VERSION 5.5 ;
NAMESCASESENSITIVE ON ;
BUSBITCHARS "[]" ;
DIVIDERCHAR "/" ;

PROPERTYDEFINITIONS
  LAYER routingPitch REAL ;
END PROPERTYDEFINITIONS

UNITS
  DATABASE MICRONS 1000 ;
END UNITS
MANUFACTURINGGRID 0.01 ;
LAYER POLY1
  TYPE MASTERSLICE ;
END POLY1

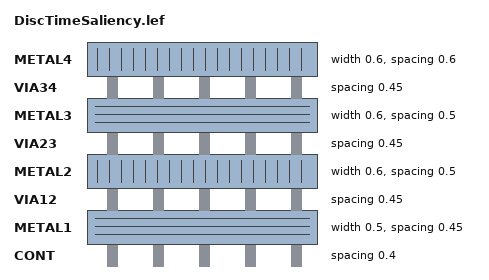
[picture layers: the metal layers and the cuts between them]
LAYER CONT
  TYPE CUT ;
  SPACING 0.4 ;
END CONT

LAYER METAL1
  TYPE ROUTING ;
  DIRECTION HORIZONTAL ;
  PITCH 0 ;
  WIDTH 0.5 ;
  SPACING 0.45 ;
  PROPERTY routingPitch 1.25 ;
END METAL1

LAYER VIA12
  TYPE CUT ;
  SPACING 0.45 ;
END VIA12

LAYER METAL2
  TYPE ROUTING ;
  DIRECTION VERTICAL ;
  PITCH 0 ;
  WIDTH 0.6 ;
  SPACING 0.5 ;
  PROPERTY routingPitch 1.4 ;
END METAL2

LAYER VIA23
  TYPE CUT ;
  SPACING 0.45 ;
END VIA23

LAYER METAL3
  TYPE ROUTING ;
  DIRECTION HORIZONTAL ;
  PITCH 0 ;
  WIDTH 0.6 ;
  SPACING 0.5 ;
  PROPERTY routingPitch 1.25 ;
END METAL3

LAYER VIA34
  TYPE CUT ;
  SPACING 0.45 ;
END VIA34

LAYER METAL4
  TYPE ROUTING ;
  DIRECTION VERTICAL ;
  PITCH 0 ;
  WIDTH 0.6 ;
  SPACING 0.6 ;
  PROPERTY routingPitch 1.4 ;
END METAL4

LAYER OVERLAP
  TYPE OVERLAP ;
END OVERLAP

VIARULE M4_M3 GENERATE
  LAYER METAL3 ;
    ENCLOSURE 0.2 0.2 ;
  LAYER METAL4 ;
    ENCLOSURE 0.15 0.15 ;
  LAYER VIA34 ;
    RECT -0.25 -0.25 0.25 0.25 ;
    SPACING 1 BY 1 ;
END M4_M3

VIARULE M3_M2 GENERATE
  LAYER METAL2 ;
    ENCLOSURE 0.2 0.2 ;
  LAYER METAL3 ;
    ENCLOSURE 0.15 0.15 ;
  LAYER VIA23 ;
    RECT -0.25 -0.25 0.25 0.25 ;
    SPACING 1 BY 1 ;
END M3_M2

VIARULE M2_M1 GENERATE
  LAYER METAL1 ;
    ENCLOSURE 0.2 0.2 ;
  LAYER METAL2 ;
    ENCLOSURE 0.15 0.15 ;
  LAYER VIA12 ;
    RECT -0.25 -0.25 0.25 0.25 ;
    SPACING 1 BY 1 ;
END M2_M1

VIARULE M1_POLY1 GENERATE
  LAYER POLY1 ;
    ENCLOSURE 0.2 0.2 ;
  LAYER METAL1 ;
    ENCLOSURE 0.15 0.15 ;
  LAYER CONT ;
    RECT -0.2 -0.2 0.2 0.2 ;
    SPACING 1 BY 1 ;
END M1_POLY1

VIA M1_POLY1
  LAYER CONT ;
    RECT -0.2 -0.2 0.2 0.2 ;
  LAYER POLY1 ;
    RECT -0.4 -0.4 0.4 0.4 ;
  LAYER METAL1 ;
    RECT -0.35 -0.35 0.35 0.35 ;
END M1_POLY1

VIA M2_M1
  LAYER VIA12 ;
    RECT -0.25 -0.25 0.25 0.25 ;
  LAYER METAL2 ;
    RECT -0.4 -0.4 0.4 0.4 ;
  LAYER METAL1 ;
    RECT -0.45 -0.45 0.45 0.45 ;
END M2_M1

VIA M3_M2
  LAYER VIA23 ;
    RECT -0.25 -0.25 0.25 0.25 ;
  LAYER METAL3 ;
    RECT -0.4 -0.4 0.4 0.4 ;
  LAYER METAL2 ;
    RECT -0.45 -0.45 0.45 0.45 ;
END M3_M2

VIA M4_M3
  LAYER VIA34 ;
    RECT -0.25 -0.25 0.25 0.25 ;
  LAYER METAL4 ;
    RECT -0.4 -0.4 0.4 0.4 ;
  LAYER METAL3 ;
    RECT -0.45 -0.45 0.45 0.45 ;
END M4_M3


MACRO TSMC350nm_VinjDecode2to4_vtile_spacing
END TSMC350nm_VinjDecode2to4_vtile_spacing

MACRO TSMC350nm_VinjDecode2to4_vtile_C_bridge
END TSMC350nm_VinjDecode2to4_vtile_C_bridge

MACRO TSMC350nm_VinjDecode2to4_vtile
  PIN Vinj
    DIRECTION INOUT ;
    USE SIGNAL ;
    PORT
      LAYER METAL1 ;
        RECT 7.78 11.04 9.06 11.45 ;
    END
  END Vinj
  PIN OUT<0>
    DIRECTION INOUT ;
    USE SIGNAL ;
    PORT
      LAYER METAL1 ;
        RECT 19.66 18.91 20.11 19.59 ;
    END
  END OUT<0>
  PIN OUT<1>
    DIRECTION INOUT ;
    USE SIGNAL ;
    PORT
      LAYER METAL1 ;
        RECT 19.66 13.41 20.12 14.1 ;
    END
  END OUT<1>
  PIN OUT<2>
    DIRECTION INOUT ;
    USE SIGNAL ;
    PORT
      LAYER METAL1 ;
        RECT 19.66 7.92 20.11 8.59 ;
    END
  END OUT<2>
  PIN OUT<3>
    DIRECTION INOUT ;
    USE SIGNAL ;
    PORT
      LAYER METAL1 ;
        RECT 19.66 2.41 20.11 3.09 ;
    END
  END OUT<3>
  PIN ENABLE
    DIRECTION INOUT ;
    USE SIGNAL ;
    PORT
      LAYER METAL1 ;
        RECT 0.01 3.48 0.71 4.21 ;
    END
  END ENABLE
  PIN GND
    DIRECTION INOUT ;
    USE SIGNAL ;
    PORT
      LAYER METAL1 ;
        RECT 19.52 5.0 20.12 5.99 ;
    END
  END GND
  PIN VINJ
    DIRECTION INOUT ;
    USE SIGNAL ;
    PORT
      LAYER METAL1 ;
        RECT 19.15 21.56 20.05 21.96 ;
    END
  END VINJ
  PIN IN<1>
    DIRECTION INOUT ;
    USE SIGNAL ;
    PORT
      LAYER METAL2 ;
        RECT 6.56 20.89 7.5 22.0 ;
    END
  END IN<1>
  PIN IN<0>
    DIRECTION INOUT ;
    USE SIGNAL ;
    PORT
      LAYER METAL2 ;
        RECT 3.9 20.96 4.5 22.0 ;
    END
  END IN<0>
END TSMC350nm_VinjDecode2to4_vtile

MACRO TSMC350nm_VinjDecode2to4_vtile_A_bridge
END TSMC350nm_VinjDecode2to4_vtile_A_bridge

MACRO TSMC350nm_VinjDecode2to4_vtile_bridge_spacing
END TSMC350nm_VinjDecode2to4_vtile_bridge_spacing

MACRO TSMC350nm_VinjDecode2to4_vtile_D_bridge
END TSMC350nm_VinjDecode2to4_vtile_D_bridge

MACRO TSMC350nm_VinjDecode2to4_vtile_B_bridge
END TSMC350nm_VinjDecode2to4_vtile_B_bridge

MACRO TSMC350nm_drainSelect01d3
  PIN Vinj
    DIRECTION INOUT ;
    USE SIGNAL ;
    PORT
      LAYER METAL1 ;
        RECT 6.12 21.55 7.4 21.96 ;
    END
  END Vinj
  PIN VINJ
    DIRECTION INOUT ;
    USE SIGNAL ;
    PORT
      LAYER METAL1 ;
        RECT 6.12 21.55 7.4 21.96 ;
    END
  END VINJ
  PIN GND
    DIRECTION INOUT ;
    USE SIGNAL ;
    PORT
      LAYER METAL1 ;
        RECT 8.76 16.56 9.51 16.97 ;
    END
  END GND
  PIN DRAIN4
    DIRECTION INOUT ;
    USE SIGNAL ;
    PORT
      LAYER METAL1 ;
        RECT 15.99 2.54 16.66 2.97 ;
    END
  END DRAIN4
  PIN DRAIN3
    DIRECTION INOUT ;
    USE SIGNAL ;
    PORT
      LAYER METAL1 ;
        RECT 15.99 8.03 16.66 8.46 ;
    END
  END DRAIN3
  PIN DRAIN2
    DIRECTION INOUT ;
    USE SIGNAL ;
    PORT
      LAYER METAL1 ;
        RECT 15.99 13.54 16.66 13.97 ;
    END
  END DRAIN2
  PIN DRAIN1
    DIRECTION INOUT ;
    USE SIGNAL ;
    PORT
      LAYER METAL1 ;
        RECT 15.99 19.03 16.66 19.46 ;
    END
  END DRAIN1
  PIN SELECT<3>
    DIRECTION INOUT ;
    USE SIGNAL ;
    PORT
      LAYER METAL1 ;
        RECT 0.0 2.54 0.67 2.97 ;
    END
  END SELECT<3>
  PIN SELET<2>
    DIRECTION INOUT ;
    USE SIGNAL ;
    PORT
      LAYER METAL1 ;
        RECT 0.0 8.03 0.67 8.46 ;
    END
  END SELET<2>
  PIN SELECT<1>
    DIRECTION INOUT ;
    USE SIGNAL ;
    PORT
      LAYER METAL1 ;
        RECT 0.0 13.54 0.67 13.97 ;
    END
  END SELECT<1>
  PIN SELECT<0>
    DIRECTION INOUT ;
    USE SIGNAL ;
    PORT
      LAYER METAL1 ;
        RECT 0.0 19.03 0.67 19.46 ;
    END
  END SELECT<0>
  PIN DRAINRAIL
    DIRECTION INOUT ;
    USE SIGNAL ;
    PORT
      LAYER METAL2 ;
        RECT 7.47 21.56 8.25 21.99 ;
    END
  END DRAINRAIL
END TSMC350nm_drainSelect01d3

MACRO TSMC350nm_FourTgate_ThickOx_FG_MEM
  PIN B<2>
    DIRECTION INOUT ;
    USE SIGNAL ;
    PORT
      LAYER METAL1 ;
        RECT 9.75 7.01 10.31 7.44 ;
    END
  END B<2>
  PIN A<2>
    DIRECTION INOUT ;
    USE SIGNAL ;
    PORT
      LAYER METAL1 ;
        RECT 0.0 8.0 0.7 8.5 ;
    END
  END A<2>
  PIN B<3>
    DIRECTION INOUT ;
    USE SIGNAL ;
    PORT
      LAYER METAL1 ;
        RECT 9.75 2.15 10.31 2.58 ;
    END
  END B<3>
  PIN A<3>
    DIRECTION INOUT ;
    USE SIGNAL ;
    PORT
      LAYER METAL1 ;
        RECT 0.0 2.5 0.7 3.0 ;
    END
  END A<3>
  PIN GND
    DIRECTION INOUT ;
    USE SIGNAL ;
    PORT
      LAYER METAL1 ;
        RECT 1.61 16.56 2.36 16.97 ;
    END
  END GND
  PIN B<0>
    DIRECTION INOUT ;
    USE SIGNAL ;
    PORT
      LAYER METAL1 ;
        RECT 9.75 20.33 10.31 20.76 ;
    END
  END B<0>
  PIN A<0>
    DIRECTION INOUT ;
    USE SIGNAL ;
    PORT
      LAYER METAL1 ;
        RECT 0.0 19.0 0.7 19.5 ;
    END
  END A<0>
  PIN B<1>
    DIRECTION INOUT ;
    USE SIGNAL ;
    PORT
      LAYER METAL1 ;
        RECT 9.75 14.73 10.31 15.16 ;
    END
  END B<1>
  PIN A<1>
    DIRECTION INOUT ;
    USE SIGNAL ;
    PORT
      LAYER METAL1 ;
        RECT 0.0 13.5 0.7 14.0 ;
    END
  END A<1>
  PIN SelBar
    DIRECTION INOUT ;
    USE SIGNAL ;
    PORT
      LAYER METAL2 ;
        RECT 3.41 21.12 4.21 22.0 ;
    END
  END SelBar
  PIN Sel
    DIRECTION INOUT ;
    USE SIGNAL ;
    PORT
      LAYER METAL2 ;
        RECT 4.8 21.12 5.6 22.0 ;
    END
  END Sel
  PIN VINJ
    DIRECTION INOUT ;
    USE SIGNAL ;
    PORT
      LAYER METAL2 ;
        RECT 6.26 21.78 7.06 22.0 ;
    END
  END VINJ
END TSMC350nm_FourTgate_ThickOx_FG_MEM

MACRO TSMC350nm_IndirectSwitches
  PIN GND_T
    DIRECTION INOUT ;
    USE SIGNAL ;
    PORT
      LAYER METAL2 ;
        RECT 15.4 21.0 16.2 22.0 ;
    END
  END GND_T
  PIN VINJ_T
    DIRECTION INOUT ;
    USE SIGNAL ;
    PORT
      LAYER METAL2 ;
        RECT 6.3 21.04 7.32 22.0 ;
    END
  END VINJ_T
  PIN VDD<1>
    DIRECTION INOUT ;
    USE SIGNAL ;
    PORT
      LAYER METAL2 ;
        RECT 24.5 0.0 25.1 0.75 ;
    END
  END VDD<1>
  PIN VTUN
    DIRECTION INOUT ;
    USE SIGNAL ;
    PORT
      LAYER METAL2 ;
        RECT 13.3 0.0 13.9 0.82 ;
    END
  END VTUN
  PIN GND<0>
    DIRECTION INOUT ;
    USE SIGNAL ;
    PORT
      LAYER METAL2 ;
        RECT 11.2 0.0 11.8 0.85 ;
    END
  END GND<0>
  PIN GNDV<1>
    DIRECTION INOUT ;
    USE SIGNAL ;
    PORT
      LAYER METAL2 ;
        RECT 15.47 0.0 15.95 1.0 ;
    END
  END GNDV<1>
  PIN VINJ
    DIRECTION INOUT ;
    USE SIGNAL ;
    PORT
      LAYER METAL2 ;
        RECT 4.2 0.0 4.8 1.0 ;
    END
  END VINJ
  PIN VDD<0>
    DIRECTION INOUT ;
    USE SIGNAL ;
    PORT
      LAYER METAL2 ;
        RECT 2.1 0.0 2.7 1.09 ;
    END
  END VDD<0>
  PIN Vg<0>
    DIRECTION INOUT ;
    USE SIGNAL ;
    PORT
      LAYER METAL2 ;
        RECT 8.4 0.005 9.0 0.825 ;
    END
  END Vg<0>
  PIN CTRL_B<0>
    DIRECTION INOUT ;
    USE SIGNAL ;
    PORT
      LAYER METAL2 ;
        RECT 6.3 0.01 6.9 0.76 ;
    END
  END CTRL_B<0>
  PIN CTRL_B<1>
    DIRECTION INOUT ;
    USE SIGNAL ;
    PORT
      LAYER METAL2 ;
        RECT 20.3 0.01 20.9 0.75 ;
    END
  END CTRL_B<1>
  PIN Vg<1>
    DIRECTION INOUT ;
    USE SIGNAL ;
    PORT
      LAYER METAL2 ;
        RECT 18.2 0.0 18.8 0.76 ;
    END
  END Vg<1>
  PIN decode<0>
    DIRECTION INOUT ;
    USE SIGNAL ;
    PORT
      LAYER METAL2 ;
        RECT 3.46 21.16 4.8 22.0 ;
    END
  END decode<0>
  PIN RUN_IN<1>
    DIRECTION INOUT ;
    USE SIGNAL ;
    PORT
      LAYER METAL2 ;
        RECT 17.5 21.01 18.1 22.0 ;
    END
  END RUN_IN<1>
  PIN RUN_IN<0>
    DIRECTION INOUT ;
    USE SIGNAL ;
    PORT
      LAYER METAL2 ;
        RECT 10.5 20.9 11.1 22.0 ;
    END
  END RUN_IN<0>
  PIN VPWR<1>
    DIRECTION INOUT ;
    USE SIGNAL ;
    PORT
      LAYER METAL2 ;
        RECT 21.7 21.08 22.3 22.0 ;
    END
  END VPWR<1>
  PIN decode<1>
    DIRECTION INOUT ;
    USE SIGNAL ;
    PORT
      LAYER METAL2 ;
        RECT 23.8 21.09 25.0 22.0 ;
    END
  END decode<1>
  PIN VPWR<0>
    DIRECTION INOUT ;
    USE SIGNAL ;
    PORT
      LAYER METAL2 ;
        RECT 1.71 21.21 2.43 22.0 ;
    END
  END VPWR<0>
  PIN VTUN_T
    DIRECTION INOUT ;
    USE SIGNAL ;
    PORT
      LAYER METAL2 ;
        RECT 12.6 21.12 13.7 22.0 ;
    END
  END VTUN_T
  PIN vtun_l
    DIRECTION INOUT ;
    USE SIGNAL ;
    PORT
      LAYER METAL1 ;
        RECT 0.0 0.9 1.31 1.88 ;
    END
  END vtun_l
  PIN vtun_r
    DIRECTION INOUT ;
    USE SIGNAL ;
    PORT
      LAYER METAL1 ;
        RECT 26.17 0.9 27.46 2.17 ;
    END
  END vtun_r
  PIN vgsel_r
    DIRECTION INOUT ;
    USE SIGNAL ;
    PORT
      LAYER METAL1 ;
        RECT 26.52 3.15 27.46 4.45 ;
    END
  END vgsel_r
  PIN prog_r
    DIRECTION INOUT ;
    USE SIGNAL ;
    PORT
      LAYER METAL1 ;
        RECT 26.59 9.15 27.46 10.55 ;
    END
  END prog_r
  PIN run_r
    DIRECTION INOUT ;
    USE SIGNAL ;
    PORT
      LAYER METAL1 ;
        RECT 26.28 6.05 27.46 7.29 ;
    END
  END run_r
  PIN RUN
    DIRECTION INOUT ;
    USE SIGNAL ;
    PORT
      LAYER METAL1 ;
        RECT 0.0 6.05 0.91 7.29 ;
    END
  END RUN
  PIN PROG
    DIRECTION INOUT ;
    USE SIGNAL ;
    PORT
      LAYER METAL1 ;
        RECT 0.0 9.15 0.87 10.55 ;
    END
  END PROG
  PIN Vgsel
    DIRECTION INOUT ;
    USE SIGNAL ;
    PORT
      LAYER METAL1 ;
        RECT 0.0 3.72 0.91 4.45 ;
    END
  END Vgsel
END TSMC350nm_IndirectSwitches

MACRO TSMC350nm_VinjDecode2to4_htile
  PIN IN<1>
    DIRECTION INOUT ;
    USE SIGNAL ;
    PORT
      LAYER METAL1 ;
        RECT 0.0 11.85 0.9 12.74 ;
    END
  END IN<1>
  PIN IN<0>
    DIRECTION INOUT ;
    USE SIGNAL ;
    PORT
      LAYER METAL1 ;
        RECT 0.0 10.13 0.87 11.1 ;
    END
  END IN<0>
  PIN VINJ
    DIRECTION INOUT ;
    USE SIGNAL ;
    PORT
      LAYER METAL1 ;
        RECT 0.0 1.99 0.5 2.49 ;
    END
  END VINJ
  PIN GND
    DIRECTION INOUT ;
    USE SIGNAL ;
    PORT
      LAYER METAL1 ;
        RECT 0.0 6.99 0.51 7.49 ;
    END
  END GND
  PIN GND_b<1>
    DIRECTION INOUT ;
    USE SIGNAL ;
    PORT
      LAYER METAL2 ;
        RECT 40.32 0.0 40.92 1.79 ;
    END
  END GND_b<1>
  PIN VINJ_b<1>
    DIRECTION INOUT ;
    USE SIGNAL ;
    PORT
      LAYER METAL2 ;
        RECT 22.1 0.0 22.7 1.44 ;
    END
  END VINJ_b<1>
  PIN GND_b<0>
    DIRECTION INOUT ;
    USE SIGNAL ;
    PORT
      LAYER METAL2 ;
        RECT 18.85 0.0 19.45 1.41 ;
    END
  END GND_b<0>
  PIN VINJ_b<0>
    DIRECTION INOUT ;
    USE SIGNAL ;
    PORT
      LAYER METAL2 ;
        RECT 1.07 0.0 1.67 1.25 ;
    END
  END VINJ_b<0>
  PIN VINJV
    DIRECTION INOUT ;
    USE SIGNAL ;
    PORT
      LAYER METAL2 ;
        RECT 23.7 21.26 24.31 22.0 ;
    END
  END VINJV
  PIN GNDV
    DIRECTION INOUT ;
    USE SIGNAL ;
    PORT
      LAYER METAL2 ;
        RECT 25.84 21.28 26.44 22.0 ;
    END
  END GNDV
  PIN RUN_OUT<3>
    DIRECTION INOUT ;
    USE SIGNAL ;
    PORT
      LAYER METAL2 ;
        RECT 34.39 0.0 35.19 0.86 ;
    END
  END RUN_OUT<3>
  PIN RUN_OUT<2>
    DIRECTION INOUT ;
    USE SIGNAL ;
    PORT
      LAYER METAL2 ;
        RECT 28.77 0.0 29.57 0.86 ;
    END
  END RUN_OUT<2>
  PIN RUN_OUT<1>
    DIRECTION INOUT ;
    USE SIGNAL ;
    PORT
      LAYER METAL2 ;
        RECT 13.5 0.0 14.1 0.86 ;
    END
  END RUN_OUT<1>
  PIN RUN_OUT<0>
    DIRECTION INOUT ;
    USE SIGNAL ;
    PORT
      LAYER METAL2 ;
        RECT 7.34 0.0 8.14 0.86 ;
    END
  END RUN_OUT<0>
  PIN ENABLE
    DIRECTION INOUT ;
    USE SIGNAL ;
    PORT
      LAYER METAL2 ;
        RECT 6.29 21.66 6.89 22.0 ;
    END
  END ENABLE
  PIN OUT<2>
    DIRECTION INOUT ;
    USE SIGNAL ;
    PORT
      LAYER METAL2 ;
        RECT 25.28 0.0 25.87 0.87 ;
    END
  END OUT<2>
  PIN OUT<3>
    DIRECTION INOUT ;
    USE SIGNAL ;
    PORT
      LAYER METAL2 ;
        RECT 37.14 0.0 37.73 0.83 ;
    END
  END OUT<3>
  PIN OUT<0>
    DIRECTION INOUT ;
    USE SIGNAL ;
    PORT
      LAYER METAL2 ;
        RECT 4.27 0.0 4.87 0.86 ;
    END
  END OUT<0>
  PIN OUT<1>
    DIRECTION INOUT ;
    USE SIGNAL ;
    PORT
      LAYER METAL2 ;
        RECT 16.14 0.0 16.72 0.85 ;
    END
  END OUT<1>
  PIN VGRUN<0>
    DIRECTION INOUT ;
    USE SIGNAL ;
    PORT
      LAYER METAL2 ;
        RECT 9.1 21.59 9.7 22.0 ;
    END
  END VGRUN<0>
  PIN VGRUN<1>
    DIRECTION INOUT ;
    USE SIGNAL ;
    PORT
      LAYER METAL2 ;
        RECT 11.2 21.6 11.8 22.0 ;
    END
  END VGRUN<1>
  PIN VGRUN<2>
    DIRECTION INOUT ;
    USE SIGNAL ;
    PORT
      LAYER METAL2 ;
        RECT 28.7 21.71 29.3 22.0 ;
    END
  END VGRUN<2>
  PIN VGRUN<3>
    DIRECTION INOUT ;
    USE SIGNAL ;
    PORT
      LAYER METAL2 ;
        RECT 33.6 21.54 34.2 22.0 ;
    END
  END VGRUN<3>
END TSMC350nm_VinjDecode2to4_htile

MACRO TSMC350nm_VinjDecode2to4_htile_A_bridge
  PIN VGRUN<3>
    DIRECTION INOUT ;
    USE SIGNAL ;
    PORT
      LAYER METAL2 ;
        RECT 34.5 9.46 35.1 10.0 ;
    END
  END VGRUN<3>
  PIN VGRUN<2>
    DIRECTION INOUT ;
    USE SIGNAL ;
    PORT
      LAYER METAL2 ;
        RECT 26.6 9.56 27.2 10.0 ;
    END
  END VGRUN<2>
  PIN VGRUN<1>
    DIRECTION INOUT ;
    USE SIGNAL ;
    PORT
      LAYER METAL2 ;
        RECT 13.5 9.46 14.1 10.0 ;
    END
  END VGRUN<1>
  PIN VGRUN<0>
    DIRECTION INOUT ;
    USE SIGNAL ;
    PORT
      LAYER METAL2 ;
        RECT 5.6 9.52 6.2 10.0 ;
    END
  END VGRUN<0>
END TSMC350nm_VinjDecode2to4_htile_A_bridge

MACRO TSMC350nm_VinjDecode2to4_htile_B_bridge
  PIN VGRUN<0>
    DIRECTION INOUT ;
    USE SIGNAL ;
    PORT
      LAYER METAL2 ;
        RECT 9.1 9.52 9.7 10.0 ;
    END
  END VGRUN<0>
  PIN VGRUN<1>
    DIRECTION INOUT ;
    USE SIGNAL ;
    PORT
      LAYER METAL2 ;
        RECT 11.2 9.52 11.8 10.0 ;
    END
  END VGRUN<1>
  PIN VGRUN<2>
    DIRECTION INOUT ;
    USE SIGNAL ;
    PORT
      LAYER METAL2 ;
        RECT 28.7 9.5 29.3 10.0 ;
    END
  END VGRUN<2>
  PIN VGRUN<3>
    DIRECTION INOUT ;
    USE SIGNAL ;
    PORT
      LAYER METAL2 ;
        RECT 33.6 9.51 34.2 10.0 ;
    END
  END VGRUN<3>
END TSMC350nm_VinjDecode2to4_htile_B_bridge

MACRO TSMC350nm_VinjDecode2to4_htile_C_bridge
  PIN VGRUN<0>
    DIRECTION INOUT ;
    USE SIGNAL ;
    PORT
      LAYER METAL2 ;
        RECT 9.1 9.54 9.7 10.0 ;
    END
  END VGRUN<0>
  PIN VGRUN<1>
    DIRECTION INOUT ;
    USE SIGNAL ;
    PORT
      LAYER METAL2 ;
        RECT 11.2 9.57 11.8 10.0 ;
    END
  END VGRUN<1>
  PIN VGRUN<2>
    DIRECTION INOUT ;
    USE SIGNAL ;
    PORT
      LAYER METAL2 ;
        RECT 28.7 9.59 29.3 10.0 ;
    END
  END VGRUN<2>
  PIN VGRUN<3>
    DIRECTION INOUT ;
    USE SIGNAL ;
    PORT
      LAYER METAL2 ;
        RECT 33.6 9.57 34.2 10.0 ;
    END
  END VGRUN<3>
END TSMC350nm_VinjDecode2to4_htile_C_bridge

MACRO TSMC350nm_VinjDecode2to4_htile_D_bridge
  PIN VGRUN<0>
    DIRECTION INOUT ;
    USE SIGNAL ;
    PORT
      LAYER METAL2 ;
        RECT 9.1 9.58 9.7 10.0 ;
    END
  END VGRUN<0>
  PIN VGRUN<1>
    DIRECTION INOUT ;
    USE SIGNAL ;
    PORT
      LAYER METAL2 ;
        RECT 11.2 9.55 11.8 10.0 ;
    END
  END VGRUN<1>
  PIN VGRUN<2>
    DIRECTION INOUT ;
    USE SIGNAL ;
    PORT
      LAYER METAL2 ;
        RECT 28.7 9.58 29.3 10.0 ;
    END
  END VGRUN<2>
  PIN VGRUN<3>
    DIRECTION INOUT ;
    USE SIGNAL ;
    PORT
      LAYER METAL2 ;
        RECT 33.6 9.57 34.2 10.0 ;
    END
  END VGRUN<3>
END TSMC350nm_VinjDecode2to4_htile_D_bridge

MACRO TSMC350nm_VinjDecode2to4_htile_spacing
  PIN VGRUN<0>
    DIRECTION INOUT ;
    USE SIGNAL ;
    PORT
      LAYER METAL2 ;
        RECT 9.1 21.59 9.7 22.0 ;
    END
  END VGRUN<0>
  PIN VGRUN<1>
    DIRECTION INOUT ;
    USE SIGNAL ;
    PORT
      LAYER METAL2 ;
        RECT 11.2 21.52 11.8 22.0 ;
    END
  END VGRUN<1>
  PIN VGRUN<2>
    DIRECTION INOUT ;
    USE SIGNAL ;
    PORT
      LAYER METAL2 ;
        RECT 28.7 21.54 29.3 22.0 ;
    END
  END VGRUN<2>
  PIN VGRUN<3>
    DIRECTION INOUT ;
    USE SIGNAL ;
    PORT
      LAYER METAL2 ;
        RECT 33.6 21.55 34.2 22.0 ;
    END
  END VGRUN<3>
END TSMC350nm_VinjDecode2to4_htile_spacing

MACRO TSMC350nm_VinjDecode2to4_htile_bridge_spacing
  PIN VGRUN<0>
    DIRECTION INOUT ;
    USE SIGNAL ;
    PORT
      LAYER METAL2 ;
        RECT 9.1 9.52 9.7 9.99 ;
    END
  END VGRUN<0>
  PIN VGRUN<1>
    DIRECTION INOUT ;
    USE SIGNAL ;
    PORT
      LAYER METAL2 ;
        RECT 11.2 9.51 11.8 9.99 ;
    END
  END VGRUN<1>
  PIN VGRUN<2>
    DIRECTION INOUT ;
    USE SIGNAL ;
    PORT
      LAYER METAL2 ;
        RECT 28.7 9.41 29.3 9.99 ;
    END
  END VGRUN<2>
  PIN VGRUN<3>
    DIRECTION INOUT ;
    USE SIGNAL ;
    PORT
      LAYER METAL2 ;
        RECT 33.6 9.47 34.2 9.99 ;
    END
  END VGRUN<3>
END TSMC350nm_VinjDecode2to4_htile_bridge_spacing

MACRO SampleControl
  PIN Sample
    DIRECTION INOUT ;
    USE SIGNAL ;
    PORT
      LAYER METAL1 ;
        RECT 0.0 30.1 1.4 31.5 ;
    END
  END Sample
  PIN VDD
    DIRECTION INOUT ;
    USE SIGNAL ;
    PORT
      LAYER METAL1 ;
        RECT 0.0 36.65 1.4 38.05 ;
    END
  END VDD
  PIN Q
    DIRECTION INOUT ;
    USE SIGNAL ;
    PORT
      LAYER METAL2 ;
        RECT 22.2 14.85 22.8 15.45 ;
    END
  END Q
  PIN CLK
    DIRECTION INOUT ;
    USE SIGNAL ;
    PORT
      LAYER METAL2 ;
        RECT 0.0 12.75 0.6 13.35 ;
    END
  END CLK
  PIN D
    DIRECTION INOUT ;
    USE SIGNAL ;
    PORT
      LAYER METAL2 ;
        RECT 0.0 14.85 0.6 15.45 ;
    END
  END D
  PIN GND
    DIRECTION INOUT ;
    USE SIGNAL ;
    PORT
      LAYER METAL2 ;
        RECT 13.08 39.4 13.68 40.0 ;
    END
  END GND
  PIN phi2
    DIRECTION INOUT ;
    USE SIGNAL ;
    PORT
      LAYER METAL2 ;
        RECT 11.45 39.4 12.05 40.0 ;
    END
  END phi2
  PIN phi1
    DIRECTION INOUT ;
    USE SIGNAL ;
    PORT
      LAYER METAL2 ;
        RECT 2.1 39.4 2.7 40.0 ;
    END
  END phi1
END SampleControl

MACRO tile_analog_frame
  PIN n_Prog
    DIRECTION INOUT ;
    USE SIGNAL ;
    PORT
      LAYER METAL3 ;
        RECT 13.3 3722.3 14.7 3725.1 ;
    END
  END n_Prog
  PIN n_RUN
    DIRECTION INOUT ;
    USE SIGNAL ;
    PORT
      LAYER METAL3 ;
        RECT 27.3 3722.3 28.7 3725.1 ;
    END
  END n_RUN
  PIN n_VGPROG
    DIRECTION INOUT ;
    USE SIGNAL ;
    PORT
      LAYER METAL3 ;
        RECT 41.3 3722.3 42.7 3725.1 ;
    END
  END n_VGPROG
  PIN n_avdd
    DIRECTION INOUT ;
    USE SIGNAL ;
    PORT
      LAYER METAL3 ;
        RECT 5747.51 3722.3 5748.91 3725.1 ;
    END
  END n_avdd
  PIN n_gnd
    DIRECTION INOUT ;
    USE SIGNAL ;
    PORT
      LAYER METAL3 ;
        RECT 5733.51 3722.3 5734.91 3725.1 ;
    END
  END n_gnd
  PIN n_vinj
    DIRECTION INOUT ;
    USE SIGNAL ;
    PORT
      LAYER METAL3 ;
        RECT 5719.51 3722.3 5720.91 3725.1 ;
    END
  END n_vinj
  PIN n_Q_enable
    DIRECTION INOUT ;
    USE SIGNAL ;
    PORT
      LAYER METAL3 ;
        RECT 55.3 3722.3 56.7 3725.1 ;
    END
  END n_Q_enable
  PIN e_vbias
    DIRECTION INOUT ;
    USE SIGNAL ;
    PORT
      LAYER METAL3 ;
        RECT 5774.11 3709.7 5776.91 3711.1 ;
    END
  END e_vbias
  PIN e_vdbias
    DIRECTION INOUT ;
    USE SIGNAL ;
    PORT
      LAYER METAL3 ;
        RECT 5774.11 3695.7 5776.91 3697.1 ;
    END
  END e_vdbias
  PIN e_vgbias
    DIRECTION INOUT ;
    USE SIGNAL ;
    PORT
      LAYER METAL3 ;
        RECT 5774.11 3681.7 5776.91 3683.1 ;
    END
  END e_vgbias
  PIN s_avdd
    DIRECTION INOUT ;
    USE SIGNAL ;
    PORT
      LAYER METAL3 ;
        RECT 5747.51 0.0 5748.91 2.8 ;
    END
  END s_avdd
  PIN s_gnd
    DIRECTION INOUT ;
    USE SIGNAL ;
    PORT
      LAYER METAL3 ;
        RECT 5733.51 0.0 5734.91 2.8 ;
    END
  END s_gnd
  PIN s_vinj
    DIRECTION INOUT ;
    USE SIGNAL ;
    PORT
      LAYER METAL3 ;
        RECT 5719.51 0.0 5720.91 2.8 ;
    END
  END s_vinj
  PIN s_CLK
    DIRECTION INOUT ;
    USE SIGNAL ;
    PORT
      LAYER METAL3 ;
        RECT 13.3 0.0 14.7 2.8 ;
    END
  END s_CLK
  PIN s_Sample
    DIRECTION INOUT ;
    USE SIGNAL ;
    PORT
      LAYER METAL3 ;
        RECT 27.3 0.0 28.7 2.8 ;
    END
  END s_Sample
  PIN s_Q
    DIRECTION INOUT ;
    USE SIGNAL ;
    PORT
      LAYER METAL3 ;
        RECT 41.3 0.0 42.7 2.8 ;
    END
  END s_Q
  PIN s_D
    DIRECTION INOUT ;
    USE SIGNAL ;
    PORT
      LAYER METAL3 ;
        RECT 55.3 0.0 56.7 2.8 ;
    END
  END s_D
END tile_analog_frame

MACRO dotproduct_mid
  PIN phi1_B
    DIRECTION INOUT ;
    USE SIGNAL ;
    PORT
      LAYER METAL2 ;
        RECT 2.1 0.0 2.7 0.6 ;
    END
  END phi1_B
  PIN GND_B
    DIRECTION INOUT ;
    USE SIGNAL ;
    PORT
      LAYER METAL2 ;
        RECT 13.08 0.0 13.68 0.6 ;
    END
  END GND_B
  PIN phi2_B
    DIRECTION INOUT ;
    USE SIGNAL ;
    PORT
      LAYER METAL2 ;
        RECT 11.45 0.0 12.05 0.6 ;
    END
  END phi2_B
  PIN GND
    DIRECTION INOUT ;
    USE SIGNAL ;
    PORT
      LAYER METAL2 ;
        RECT 13.08 21.4 13.68 22.0 ;
    END
  END GND
  PIN out2
    DIRECTION INOUT ;
    USE SIGNAL ;
    PORT
      LAYER METAL2 ;
        RECT 17.05 21.4 17.65 22.0 ;
    END
  END out2
  PIN out1
    DIRECTION INOUT ;
    USE SIGNAL ;
    PORT
      LAYER METAL2 ;
        RECT 6.95 21.4 7.55 22.0 ;
    END
  END out1
  PIN phi2
    DIRECTION INOUT ;
    USE SIGNAL ;
    PORT
      LAYER METAL2 ;
        RECT 11.45 21.4 12.05 22.0 ;
    END
  END phi2
  PIN phi1
    DIRECTION INOUT ;
    USE SIGNAL ;
    PORT
      LAYER METAL2 ;
        RECT 2.1 21.4 2.7 22.0 ;
    END
  END phi1
  PIN Q<0>
    DIRECTION INOUT ;
    USE SIGNAL ;
    PORT
      LAYER METAL1 ;
        RECT 0.0 16.61 1.4 18.01 ;
    END
  END Q<0>
  PIN Q<3>
    DIRECTION INOUT ;
    USE SIGNAL ;
    PORT
      LAYER METAL1 ;
        RECT 0.0 4.01 1.4 5.41 ;
    END
  END Q<3>
  PIN Q<1>
    DIRECTION INOUT ;
    USE SIGNAL ;
    PORT
      LAYER METAL1 ;
        RECT 0.0 14.76 1.4 16.16 ;
    END
  END Q<1>
  PIN Q<2>
    DIRECTION INOUT ;
    USE SIGNAL ;
    PORT
      LAYER METAL1 ;
        RECT 0.0 5.86 1.4 7.26 ;
    END
  END Q<2>
  PIN K<2>
    DIRECTION INOUT ;
    USE SIGNAL ;
    PORT
      LAYER METAL1 ;
        RECT 20.6 9.31 22.0 10.71 ;
    END
  END K<2>
  PIN K<1>
    DIRECTION INOUT ;
    USE SIGNAL ;
    PORT
      LAYER METAL1 ;
        RECT 20.6 11.31 22.0 12.71 ;
    END
  END K<1>
  PIN K<3>
    DIRECTION INOUT ;
    USE SIGNAL ;
    PORT
      LAYER METAL1 ;
        RECT 20.6 0.56 22.0 1.96 ;
    END
  END K<3>
  PIN K<0>
    DIRECTION INOUT ;
    USE SIGNAL ;
    PORT
      LAYER METAL1 ;
        RECT 20.6 20.06 22.0 21.46 ;
    END
  END K<0>
END dotproduct_mid

MACRO TSMC350nm_4x2_Indirect
  PIN Vg<1>
    DIRECTION INOUT ;
    USE SIGNAL ;
    PORT
      LAYER METAL2 ;
        RECT 18.2 21.06 18.8 22.0 ;
    END
  END Vg<1>
  PIN Vsel<1>
    DIRECTION INOUT ;
    USE SIGNAL ;
    PORT
      LAYER METAL2 ;
        RECT 20.3 21.08 20.9 22.0 ;
    END
  END Vsel<1>
  PIN VINJ<1>
    DIRECTION INOUT ;
    USE SIGNAL ;
    PORT
      LAYER METAL2 ;
        RECT 22.4 21.05 23.0 22.0 ;
    END
  END VINJ<1>
  PIN Vsel<0>
    DIRECTION INOUT ;
    USE SIGNAL ;
    PORT
      LAYER METAL2 ;
        RECT 6.3 21.2 6.9 22.0 ;
    END
  END Vsel<0>
  PIN Vs<0>
    DIRECTION INOUT ;
    USE SIGNAL ;
    PORT
      LAYER METAL2 ;
        RECT 2.1 21.21 2.7 22.0 ;
    END
  END Vs<0>
  PIN Vs<1>
    DIRECTION INOUT ;
    USE SIGNAL ;
    PORT
      LAYER METAL2 ;
        RECT 24.5 21.06 25.1 22.0 ;
    END
  END Vs<1>
  PIN VTUN
    DIRECTION INOUT ;
    USE SIGNAL ;
    PORT
      LAYER METAL2 ;
        RECT 13.3 21.09 13.9 22.0 ;
    END
  END VTUN
  PIN VINJ<0>
    DIRECTION INOUT ;
    USE SIGNAL ;
    PORT
      LAYER METAL2 ;
        RECT 4.2 21.18 4.8 22.0 ;
    END
  END VINJ<0>
  PIN GND<0>
    DIRECTION INOUT ;
    USE SIGNAL ;
    PORT
      LAYER METAL2 ;
        RECT 11.2 21.07 11.8 22.0 ;
    END
  END GND<0>
  PIN Vg<0>
    DIRECTION INOUT ;
    USE SIGNAL ;
    PORT
      LAYER METAL2 ;
        RECT 8.4 21.03 9.0 22.0 ;
    END
  END Vg<0>
  PIN GND<1>
    DIRECTION INOUT ;
    USE SIGNAL ;
    PORT
      LAYER METAL2 ;
        RECT 15.41 21.06 16.01 22.0 ;
    END
  END GND<1>
  PIN Vs_b<0>
    DIRECTION INOUT ;
    USE SIGNAL ;
    PORT
      LAYER METAL2 ;
        RECT 1.42 0.0 2.7 0.6 ;
    END
  END Vs_b<0>
  PIN VINJ_b<0>
    DIRECTION INOUT ;
    USE SIGNAL ;
    PORT
      LAYER METAL2 ;
        RECT 4.2 0.0 4.8 0.76 ;
    END
  END VINJ_b<0>
  PIN Vsel_b<0>
    DIRECTION INOUT ;
    USE SIGNAL ;
    PORT
      LAYER METAL2 ;
        RECT 6.3 0.0 6.9 0.78 ;
    END
  END Vsel_b<0>
  PIN Vg_b<0>
    DIRECTION INOUT ;
    USE SIGNAL ;
    PORT
      LAYER METAL2 ;
        RECT 8.4 0.0 9.0 0.77 ;
    END
  END Vg_b<0>
  PIN GND_b<0>
    DIRECTION INOUT ;
    USE SIGNAL ;
    PORT
      LAYER METAL2 ;
        RECT 11.2 0.0 11.8 0.76 ;
    END
  END GND_b<0>
  PIN VTUN_b
    DIRECTION INOUT ;
    USE SIGNAL ;
    PORT
      LAYER METAL2 ;
        RECT 13.3 0.0 13.9 0.76 ;
    END
  END VTUN_b
  PIN GND_b<1>
    DIRECTION INOUT ;
    USE SIGNAL ;
    PORT
      LAYER METAL2 ;
        RECT 15.41 0.0 16.01 0.83 ;
    END
  END GND_b<1>
  PIN Vg_b<1>
    DIRECTION INOUT ;
    USE SIGNAL ;
    PORT
      LAYER METAL2 ;
        RECT 18.2 0.0 18.8 0.76 ;
    END
  END Vg_b<1>
  PIN Vsel_b<1>
    DIRECTION INOUT ;
    USE SIGNAL ;
    PORT
      LAYER METAL2 ;
        RECT 20.3 0.0 20.9 0.75 ;
    END
  END Vsel_b<1>
  PIN VINJ_b<1>
    DIRECTION INOUT ;
    USE SIGNAL ;
    PORT
      LAYER METAL2 ;
        RECT 22.4 0.0 23.0 0.77 ;
    END
  END VINJ_b<1>
  PIN Vs_b<1>
    DIRECTION INOUT ;
    USE SIGNAL ;
    PORT
      LAYER METAL2 ;
        RECT 24.5 0.0 25.75 0.61 ;
    END
  END Vs_b<1>
  PIN Vd_Pl<3>
    DIRECTION INOUT ;
    USE SIGNAL ;
    PORT
      LAYER METAL1 ;
        RECT 0.0 0.7 1.47 1.2 ;
    END
  END Vd_Pl<3>
  PIN Vd_Rl<3>
    DIRECTION INOUT ;
    USE SIGNAL ;
    PORT
      LAYER METAL1 ;
        RECT 0.0 3.5 1.45 4.0 ;
    END
  END Vd_Rl<3>
  PIN Vd_Rl<2>
    DIRECTION INOUT ;
    USE SIGNAL ;
    PORT
      LAYER METAL1 ;
        RECT 0.0 7.0 1.4 7.5 ;
    END
  END Vd_Rl<2>
  PIN Vd_Pl<2>
    DIRECTION INOUT ;
    USE SIGNAL ;
    PORT
      LAYER METAL1 ;
        RECT 0.0 9.8 1.41 10.3 ;
    END
  END Vd_Pl<2>
  PIN Vd_Pl<1>
    DIRECTION INOUT ;
    USE SIGNAL ;
    PORT
      LAYER METAL1 ;
        RECT 0.0 11.89 1.43 12.4 ;
    END
  END Vd_Pl<1>
  PIN Vd_Rl<1>
    DIRECTION INOUT ;
    USE SIGNAL ;
    PORT
      LAYER METAL1 ;
        RECT 0.0 14.7 1.46 15.2 ;
    END
  END Vd_Rl<1>
  PIN Vd_Rl<0>
    DIRECTION INOUT ;
    USE SIGNAL ;
    PORT
      LAYER METAL1 ;
        RECT 0.0 17.5 1.43 18.0 ;
    END
  END Vd_Rl<0>
  PIN Vd_Pl<0>
    DIRECTION INOUT ;
    USE SIGNAL ;
    PORT
      LAYER METAL1 ;
        RECT 0.0 20.3 1.4 20.9 ;
    END
  END Vd_Pl<0>
  PIN Vd_P<0>
    DIRECTION INOUT ;
    USE SIGNAL ;
    PORT
      LAYER METAL1 ;
        RECT 26.63 20.3 27.46 20.8 ;
    END
  END Vd_P<0>
  PIN Vd_R<1>
    DIRECTION INOUT ;
    USE SIGNAL ;
    PORT
      LAYER METAL1 ;
        RECT 26.56 14.7 27.44 15.2 ;
    END
  END Vd_R<1>
  PIN Vd_R<3>
    DIRECTION INOUT ;
    USE SIGNAL ;
    PORT
      LAYER METAL1 ;
        RECT 26.5 3.5 27.46 4.0 ;
    END
  END Vd_R<3>
  PIN Vd_P<3>
    DIRECTION INOUT ;
    USE SIGNAL ;
    PORT
      LAYER METAL1 ;
        RECT 26.55 0.7 27.46 1.2 ;
    END
  END Vd_P<3>
  PIN Vd_P<1>
    DIRECTION INOUT ;
    USE SIGNAL ;
    PORT
      LAYER METAL1 ;
        RECT 26.38 11.9 27.46 12.4 ;
    END
  END Vd_P<1>
  PIN Vd_P<2>
    DIRECTION INOUT ;
    USE SIGNAL ;
    PORT
      LAYER METAL1 ;
        RECT 26.51 9.8 27.46 10.3 ;
    END
  END Vd_P<2>
  PIN Vd_R<0>
    DIRECTION INOUT ;
    USE SIGNAL ;
    PORT
      LAYER METAL1 ;
        RECT 26.66 17.5 27.46 18.0 ;
    END
  END Vd_R<0>
  PIN Vd_R<2>
    DIRECTION INOUT ;
    USE SIGNAL ;
    PORT
      LAYER METAL1 ;
        RECT 26.53 7.0 27.46 7.5 ;
    END
  END Vd_R<2>
END TSMC350nm_4x2_Indirect

MACRO dotproduct_L
  PIN K<0>
    DIRECTION INOUT ;
    USE SIGNAL ;
    PORT
      LAYER METAL1 ;
        RECT 20.6 20.05 22.0 21.45 ;
    END
  END K<0>
  PIN K<1>
    DIRECTION INOUT ;
    USE SIGNAL ;
    PORT
      LAYER METAL1 ;
        RECT 20.6 11.3 22.0 12.7 ;
    END
  END K<1>
  PIN Q<2>
    DIRECTION INOUT ;
    USE SIGNAL ;
    PORT
      LAYER METAL1 ;
        RECT 0.0 6.4 1.4 7.8 ;
    END
  END Q<2>
  PIN K<3>
    DIRECTION INOUT ;
    USE SIGNAL ;
    PORT
      LAYER METAL1 ;
        RECT 20.6 0.55 22.0 1.95 ;
    END
  END K<3>
  PIN Q<3>
    DIRECTION INOUT ;
    USE SIGNAL ;
    PORT
      LAYER METAL1 ;
        RECT 0.0 3.45 1.4 4.85 ;
    END
  END Q<3>
  PIN K<2>
    DIRECTION INOUT ;
    USE SIGNAL ;
    PORT
      LAYER METAL1 ;
        RECT 20.6 9.3 22.0 10.7 ;
    END
  END K<2>
  PIN Q<1>
    DIRECTION INOUT ;
    USE SIGNAL ;
    PORT
      LAYER METAL1 ;
        RECT 0.0 14.2 1.4 15.6 ;
    END
  END Q<1>
  PIN Q<0>
    DIRECTION INOUT ;
    USE SIGNAL ;
    PORT
      LAYER METAL1 ;
        RECT 0.0 17.15 1.4 18.55 ;
    END
  END Q<0>
  PIN phi1_B
    DIRECTION INOUT ;
    USE SIGNAL ;
    PORT
      LAYER METAL2 ;
        RECT 1.35 0.0 1.95 0.6 ;
    END
  END phi1_B
  PIN GND_B
    DIRECTION INOUT ;
    USE SIGNAL ;
    PORT
      LAYER METAL2 ;
        RECT 2.6 0.0 3.2 0.6 ;
    END
  END GND_B
  PIN phi2_B
    DIRECTION INOUT ;
    USE SIGNAL ;
    PORT
      LAYER METAL2 ;
        RECT 11.45 0.0 12.05 0.6 ;
    END
  END phi2_B
  PIN phi2
    DIRECTION INOUT ;
    USE SIGNAL ;
    PORT
      LAYER METAL2 ;
        RECT 11.45 21.4 12.05 22.0 ;
    END
  END phi2
  PIN GND
    DIRECTION INOUT ;
    USE SIGNAL ;
    PORT
      LAYER METAL2 ;
        RECT 2.6 21.4 3.2 22.0 ;
    END
  END GND
  PIN phi1
    DIRECTION INOUT ;
    USE SIGNAL ;
    PORT
      LAYER METAL2 ;
        RECT 1.35 21.4 1.95 22.0 ;
    END
  END phi1
  PIN out2
    DIRECTION INOUT ;
    USE SIGNAL ;
    PORT
      LAYER METAL2 ;
        RECT 17.05 21.4 17.65 22.0 ;
    END
  END out2
  PIN out1
    DIRECTION INOUT ;
    USE SIGNAL ;
    PORT
      LAYER METAL2 ;
        RECT 6.95 21.4 7.55 22.0 ;
    END
  END out1
END dotproduct_L

MACRO TSMC350nm_HorizontalScanner
  PIN In<3>
    DIRECTION INOUT ;
    USE SIGNAL ;
    PORT
      LAYER METAL1 ;
        RECT 76.432 -69.748 77.732 -69.098 ;
    END
  END In<3>
  PIN In<2>
    DIRECTION INOUT ;
    USE SIGNAL ;
    PORT
      LAYER METAL1 ;
        RECT 79.712 -69.748 80.582 -69.058 ;
    END
  END In<2>
  PIN In<1>
    DIRECTION INOUT ;
    USE SIGNAL ;
    PORT
      LAYER METAL1 ;
        RECT 87.522 -69.748 88.492 -69.018 ;
    END
  END In<1>
  PIN In<0>
    DIRECTION INOUT ;
    USE SIGNAL ;
    PORT
      LAYER METAL1 ;
        RECT 90.252 -69.748 91.332 -69.018 ;
    END
  END In<0>
  PIN fake_pin
    DIRECTION INOUT ;
    USE SIGNAL ;
    PORT
      LAYER METAL1 ;
        RECT 84.002 -69.748 84.492 -69.118 ;
    END
  END fake_pin
  PIN Out
    DIRECTION INOUT ;
    USE SIGNAL ;
    PORT
      LAYER METAL2 ;
        RECT 73.292 -64.598 74.112 -63.098 ;
    END
  END Out
  PIN Din
    DIRECTION INOUT ;
    USE SIGNAL ;
    PORT
      LAYER METAL2 ;
        RECT 94.862 -26.948 95.292 -26.348 ;
    END
  END Din
  PIN Qout
    DIRECTION INOUT ;
    USE SIGNAL ;
    PORT
      LAYER METAL2 ;
        RECT 73.292 -26.948 73.892 -26.348 ;
    END
  END Qout
  PIN VSS
    DIRECTION INOUT ;
    USE SIGNAL ;
    PORT
      LAYER METAL2 ;
        RECT 73.292 -15.958 73.762 -14.458 ;
    END
  END VSS
  PIN VDD
    DIRECTION INOUT ;
    USE SIGNAL ;
    PORT
      LAYER METAL2 ;
        RECT 94.752 -23.888 95.292 -22.388 ;
    END
  END VDD
  PIN RSTBar
    DIRECTION INOUT ;
    USE SIGNAL ;
    PORT
      LAYER METAL2 ;
        RECT 94.922 86.452 95.292 87.052 ;
    END
  END RSTBar
  PIN CLK
    DIRECTION INOUT ;
    USE SIGNAL ;
    PORT
      LAYER METAL2 ;
        RECT 94.912 80.852 95.292 81.452 ;
    END
  END CLK
END TSMC350nm_HorizontalScanner

MACRO Q_layer_output
  PIN GND<1>
    DIRECTION INOUT ;
    USE SIGNAL ;
    PORT
      LAYER METAL2 ;
        RECT 93.05 21.4 93.65 22.0 ;
    END
  END GND<1>
  PIN Vdbias<1>
    DIRECTION INOUT ;
    USE SIGNAL ;
    PORT
      LAYER METAL2 ;
        RECT 66.59 21.4 67.19 22.0 ;
    END
  END Vdbias<1>
  PIN Vbias<1>
    DIRECTION INOUT ;
    USE SIGNAL ;
    PORT
      LAYER METAL2 ;
        RECT 63.56 21.4 64.16 22.0 ;
    END
  END Vbias<1>
  PIN VPWR<1>
    DIRECTION INOUT ;
    USE SIGNAL ;
    PORT
      LAYER METAL2 ;
        RECT 61.26 21.4 61.86 22.0 ;
    END
  END VPWR<1>
  PIN Vgbias
    DIRECTION INOUT ;
    USE SIGNAL ;
    PORT
      LAYER METAL2 ;
        RECT 57.27 21.4 57.87 22.0 ;
    END
  END Vgbias
  PIN GND<0>
    DIRECTION INOUT ;
    USE SIGNAL ;
    PORT
      LAYER METAL2 ;
        RECT 36.39 21.4 36.99 22.0 ;
    END
  END GND<0>
  PIN Vdbias<0>
    DIRECTION INOUT ;
    USE SIGNAL ;
    PORT
      LAYER METAL2 ;
        RECT 9.93 21.4 10.53 22.0 ;
    END
  END Vdbias<0>
  PIN Vbias<0>
    DIRECTION INOUT ;
    USE SIGNAL ;
    PORT
      LAYER METAL2 ;
        RECT 6.9 21.4 7.5 22.0 ;
    END
  END Vbias<0>
  PIN VPWR<0>
    DIRECTION INOUT ;
    USE SIGNAL ;
    PORT
      LAYER METAL2 ;
        RECT 4.6 21.4 5.2 22.0 ;
    END
  END VPWR<0>
  PIN Q_out<0>
    DIRECTION INOUT ;
    USE SIGNAL ;
    PORT
      LAYER METAL1 ;
        RECT 111.06 17.5 112.46 18.9 ;
    END
  END Q_out<0>
  PIN Q_out<1>
    DIRECTION INOUT ;
    USE SIGNAL ;
    PORT
      LAYER METAL1 ;
        RECT 111.06 13.8 112.46 15.2 ;
    END
  END Q_out<1>
  PIN Q_out<2>
    DIRECTION INOUT ;
    USE SIGNAL ;
    PORT
      LAYER METAL1 ;
        RECT 111.06 7.0 112.46 8.4 ;
    END
  END Q_out<2>
  PIN Q_out<3>
    DIRECTION INOUT ;
    USE SIGNAL ;
    PORT
      LAYER METAL1 ;
        RECT 111.06 2.6 112.46 4.0 ;
    END
  END Q_out<3>
  PIN Q_in<3>
    DIRECTION INOUT ;
    USE SIGNAL ;
    PORT
      LAYER METAL1 ;
        RECT 0.0 2.6 1.4 4.0 ;
    END
  END Q_in<3>
  PIN Q_in<2>
    DIRECTION INOUT ;
    USE SIGNAL ;
    PORT
      LAYER METAL1 ;
        RECT 0.0 7.0 1.4 8.4 ;
    END
  END Q_in<2>
  PIN Q_in<1>
    DIRECTION INOUT ;
    USE SIGNAL ;
    PORT
      LAYER METAL1 ;
        RECT 0.0 13.8 1.4 15.2 ;
    END
  END Q_in<1>
  PIN Q_in<0>
    DIRECTION INOUT ;
    USE SIGNAL ;
    PORT
      LAYER METAL1 ;
        RECT 0.0 17.5 1.4 18.9 ;
    END
  END Q_in<0>
END Q_layer_output

MACRO K_layer_output
  PIN GND
    DIRECTION INOUT ;
    USE SIGNAL ;
    PORT
      LAYER METAL2 ;
        RECT 5.05 21.4 5.65 22.0 ;
    END
  END GND
END K_layer_output

MACRO dotproduct_R
  PIN phi1_B
    DIRECTION INOUT ;
    USE SIGNAL ;
    PORT
      LAYER METAL2 ;
        RECT 2.1 0.0 2.7 0.6 ;
    END
  END phi1_B
  PIN GND_B
    DIRECTION INOUT ;
    USE SIGNAL ;
    PORT
      LAYER METAL2 ;
        RECT 14.71 0.0 15.31 0.6 ;
    END
  END GND_B
  PIN phi2_B
    DIRECTION INOUT ;
    USE SIGNAL ;
    PORT
      LAYER METAL2 ;
        RECT 11.45 0.0 12.05 0.6 ;
    END
  END phi2_B
  PIN GND
    DIRECTION INOUT ;
    USE SIGNAL ;
    PORT
      LAYER METAL2 ;
        RECT 14.71 21.4 15.31 22.0 ;
    END
  END GND
  PIN out2
    DIRECTION INOUT ;
    USE SIGNAL ;
    PORT
      LAYER METAL2 ;
        RECT 17.05 21.4 17.65 22.0 ;
    END
  END out2
  PIN out1
    DIRECTION INOUT ;
    USE SIGNAL ;
    PORT
      LAYER METAL2 ;
        RECT 6.95 21.4 7.55 22.0 ;
    END
  END out1
  PIN phi2
    DIRECTION INOUT ;
    USE SIGNAL ;
    PORT
      LAYER METAL2 ;
        RECT 11.45 21.4 12.05 22.0 ;
    END
  END phi2
  PIN phi1
    DIRECTION INOUT ;
    USE SIGNAL ;
    PORT
      LAYER METAL2 ;
        RECT 2.1 21.4 2.7 22.0 ;
    END
  END phi1
  PIN Q<0>
    DIRECTION INOUT ;
    USE SIGNAL ;
    PORT
      LAYER METAL1 ;
        RECT 0.0 16.61 1.4 18.01 ;
    END
  END Q<0>
  PIN Q<3>
    DIRECTION INOUT ;
    USE SIGNAL ;
    PORT
      LAYER METAL1 ;
        RECT 0.0 4.01 1.4 5.41 ;
    END
  END Q<3>
  PIN Q<1>
    DIRECTION INOUT ;
    USE SIGNAL ;
    PORT
      LAYER METAL1 ;
        RECT 0.0 14.76 1.4 16.16 ;
    END
  END Q<1>
  PIN Q<2>
    DIRECTION INOUT ;
    USE SIGNAL ;
    PORT
      LAYER METAL1 ;
        RECT 0.0 5.86 1.4 7.26 ;
    END
  END Q<2>
  PIN K<2>
    DIRECTION INOUT ;
    USE SIGNAL ;
    PORT
      LAYER METAL1 ;
        RECT 20.6 7.01 22.0 8.41 ;
    END
  END K<2>
  PIN K<1>
    DIRECTION INOUT ;
    USE SIGNAL ;
    PORT
      LAYER METAL1 ;
        RECT 20.6 13.81 22.0 15.21 ;
    END
  END K<1>
  PIN K<3>
    DIRECTION INOUT ;
    USE SIGNAL ;
    PORT
      LAYER METAL1 ;
        RECT 20.6 2.61 22.0 4.01 ;
    END
  END K<3>
  PIN K<0>
    DIRECTION INOUT ;
    USE SIGNAL ;
    PORT
      LAYER METAL1 ;
        RECT 20.6 17.51 22.0 18.91 ;
    END
  END K<0>
END dotproduct_R

END LIBRARY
